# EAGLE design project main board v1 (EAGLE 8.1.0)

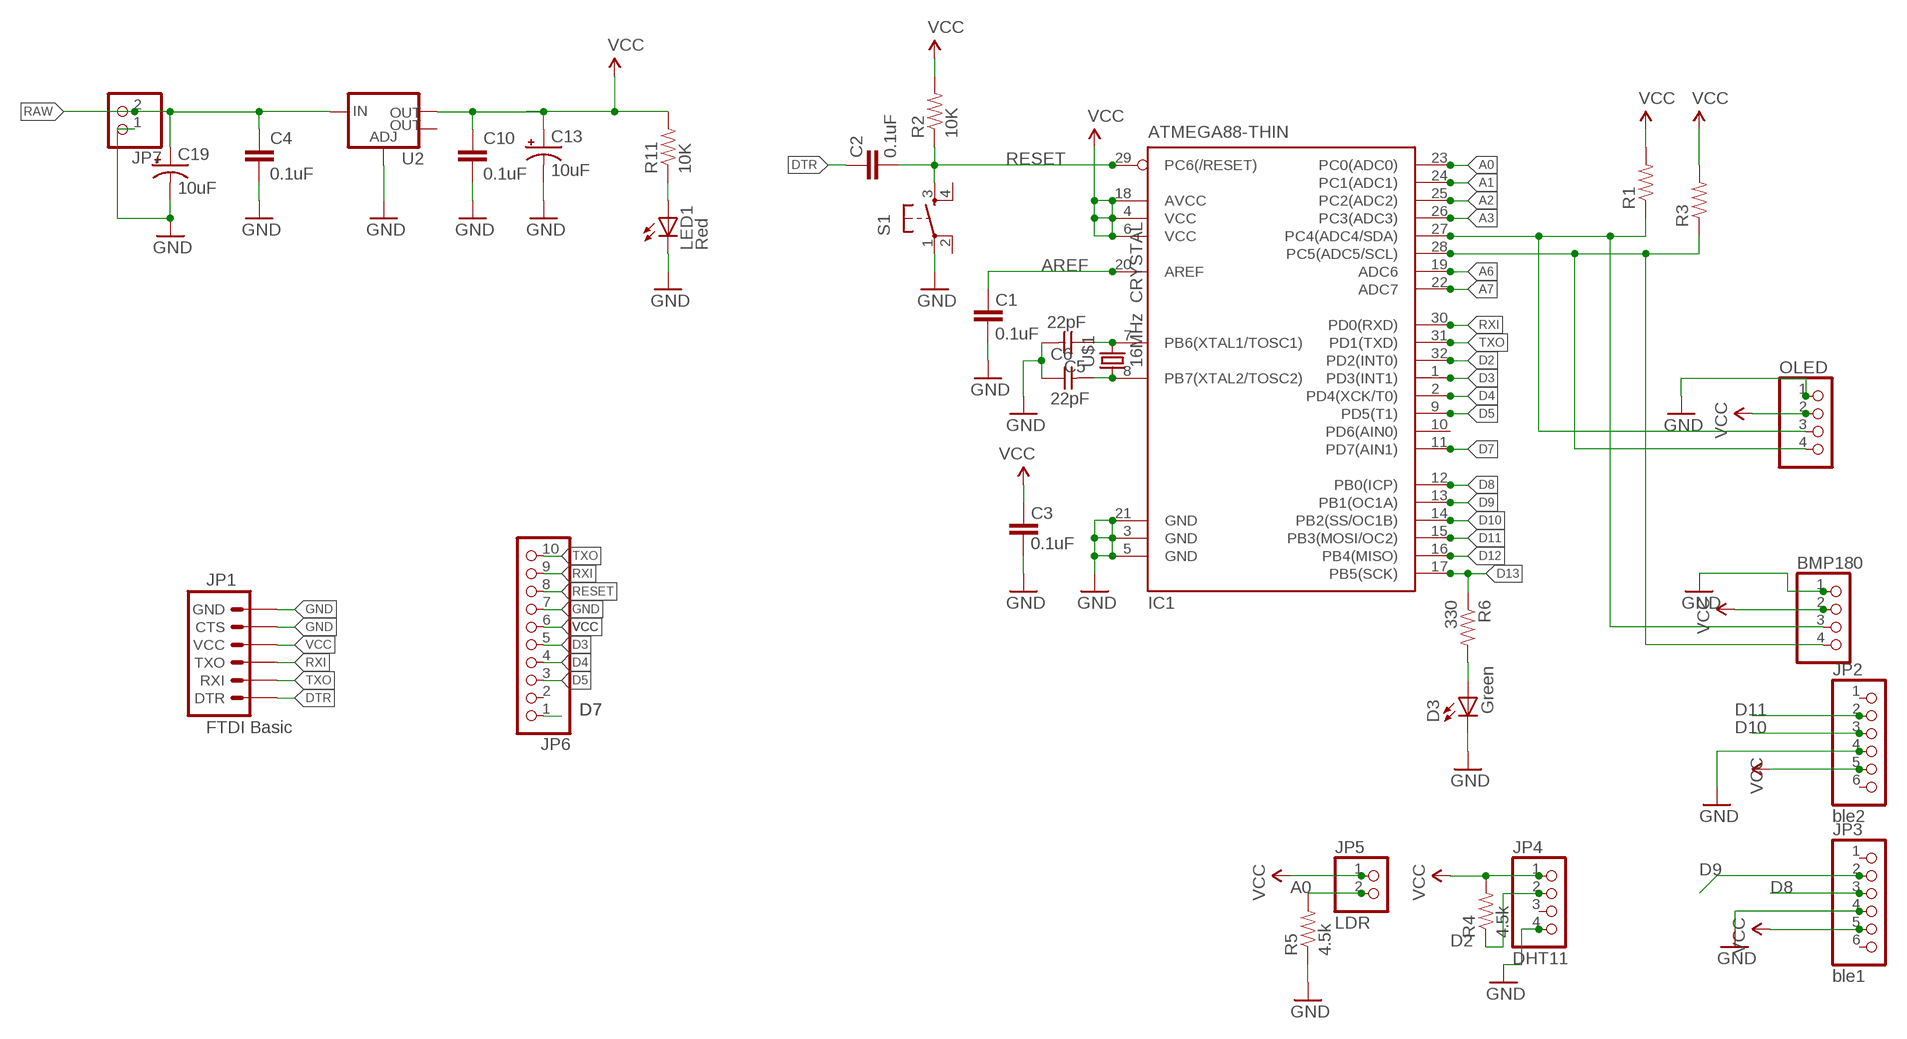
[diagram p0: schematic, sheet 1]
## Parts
BMP180  PINHD-1X4  [1X04]
C1  0.1uF  CAP1206  [1206]
C2  0.1uF  CAP1206  [1206]
C3  0.1uF  CAP1206  [1206]
C4  0.1uF  CAP1206  [1206]
C5  22pF  CAP-UNPOLARIZEDFAB  [C1206FAB]
C6  22pF  CAP-UNPOLARIZEDFAB  [C1206FAB]
C10  0.1uF  CAP1206  [1206]
C13  10uF  CAP_POL1206  [EIA3216]
C19  10uF  CAP_POL1206  [EIA3216]
D3  Green  LED1206  [LED-1206]
IC1  ATMEGA88-THIN  [TQFP32-08THIN]
JP1  FTDI Basic  ARDUINO_SERIAL_PROGRAMLONGPADS  [1X06_LONGPADS]
JP2  ble2  PINHD-1X6  [1X06]
JP3  ble1  PINHD-1X6  [1X06]
JP4  DHT11  PINHD-1X4  [1X04]
JP5  LDR  PINHD-1X2  [1X02]
JP6  PINHD-1X10  [1X10]
JP7  PINHD-1X2  [1X02]
LED1  Red  LED1206  [LED-1206]
OLED  PINHD-1X4  [1X04]
R1  RESISTOR1206  [1206]
R2  10K  RESISTOR1206  [1206]
R3  RESISTOR1206  [1206]
R4  4.5k  RESISTOR1206  [1206]
R5  4.5k  RESISTOR1206  [1206]
R6  330  RESISTOR1206  [1206]
R11  10K  RESISTOR1206  [1206]
S1  6MM_SWITCH6MM_SWITCH  [6MM_SWITCH]
U2  V_REG_LM1117SOT223  [SOT223]
U$1  16MHz CRYSTAL  CRYSTAL  [2-SMD-5X3MM]

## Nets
A0: IC1.23(PC0(ADC0)) JP5.2 R5.2
A1: IC1.24(PC1(ADC1))
A2: IC1.25(PC2(ADC2))
A3: IC1.26(PC3(ADC3))
A4: BMP180.3 IC1.27(PC4(ADC4/SDA)) OLED.3 R1.1
A5: BMP180.4 IC1.28(PC5(ADC5/SCL)) OLED.4 R3.1
A6: IC1.19(ADC6)
A7: IC1.22(ADC7)
AREF: C1.2 IC1.20(AREF)
D2: IC1.32(PD2(INT0)) JP4.2 R4.1
D3: IC1.1(PD3(INT1)) JP6.5
D4: IC1.2(PD4(XCK/T0)) JP6.4
D5: IC1.9(PD5(T1)) JP6.3
D7: IC1.11(PD7(AIN1)) JP6.1
D8: IC1.12(PB0(ICP)) JP3.3
D9: IC1.13(PB1(OC1A)) JP3.2
D10: IC1.14(PB2(SS/OC1B)) JP2.3
D11: IC1.15(PB3(MOSI/OC2)) JP2.2
D12: IC1.16(PB4(MISO))
D13: IC1.17(PB5(SCK)) R6.1
DTR: C2.2 JP1.1(DTR)
GND [vcc]: BMP180.1 C1.1 C3.1 C4.2 C5.2 C6.1 C10.2 C13.C(-) C19.C(-) D3.C IC1.3(GND) IC1.5(GND) IC1.21(GND) JP1.5(CTS) JP1.6(GND) JP2.4 JP3.4 JP4.4 JP6.7 JP7.1 LED1.C OLED.1 R5.1 S1.1(P) U2.1(ADJ)
N$1: C6.2 IC1.8(PB7(XTAL2/TOSC2)) U$1.P$1
N$2: C5.1 IC1.7(PB6(XTAL1/TOSC1)) U$1.P$2
N$3: LED1.A R11.1
N$7: D3.A R6.2
RAW [vcc]: C4.1 C19.A(+) JP7.2 U2.3(IN)
RESET: C2.1 IC1.29(PC6(/RESET)) JP6.8 R2.1 S1.3(S)
RXI: IC1.30(PD0(RXD)) JP1.3(TXO) JP6.9
TXO: IC1.31(PD1(TXD)) JP1.2(RXI) JP6.10
VCC: BMP180.2 C3.2 C10.1 C13.A(+) IC1.4(VCC) IC1.6(VCC) IC1.18(AVCC) JP1.4(VCC) JP2.5 JP3.5 JP4.1 JP5.1 JP6.6 OLED.2 R1.2 R2.2 R3.2 R4.2 R11.2 U2.2(OUT)
Unconnected: IC1.10(PD6(AIN0)) JP2.1 JP2.6 JP3.1 JP3.6 JP4.3 JP6.2 S1.2(P1) S1.4(S1) U2.4(OUT)

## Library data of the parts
BMP180 JP4 OLED = pinhead:PINHD-1X4: PIN HEADER
C1-C4 C10 = SparkFun:CAP: Capacitor
C5 C6 = fab:CAP-UNPOLARIZED
C13 C19 = SparkFun:CAP_POL: Capacitor Polarized
D3 LED1 = Testing:LED: LEDs
IC1 = fab:ATMEGA88-THIN
JP1 = SparkFun:ARDUINO_SERIAL_PROGRAM
JP2 JP3 = pinhead:PINHD-1X6: PIN HEADER
JP5 JP7 = pinhead:PINHD-1X2: PIN HEADER
JP6 = pinhead:PINHD-1X10: PIN HEADER
R1-R6 R11 = SparkFun:RESISTOR: Resistor
S1 = fab:6MM_SWITCH: OMRON SWITCH
U2 = fab:V_REG_LM1117: Voltage Regulator LM1117 Standard adjustable voltage regulator but in SMD form. Spark Fun Electronics SKU : COM-00595; PROD_ID: VREG-08170
U$1 = fab:CRYSTAL

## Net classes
0 default: width 0.203 mm
1 vcc: width 0.254 mm

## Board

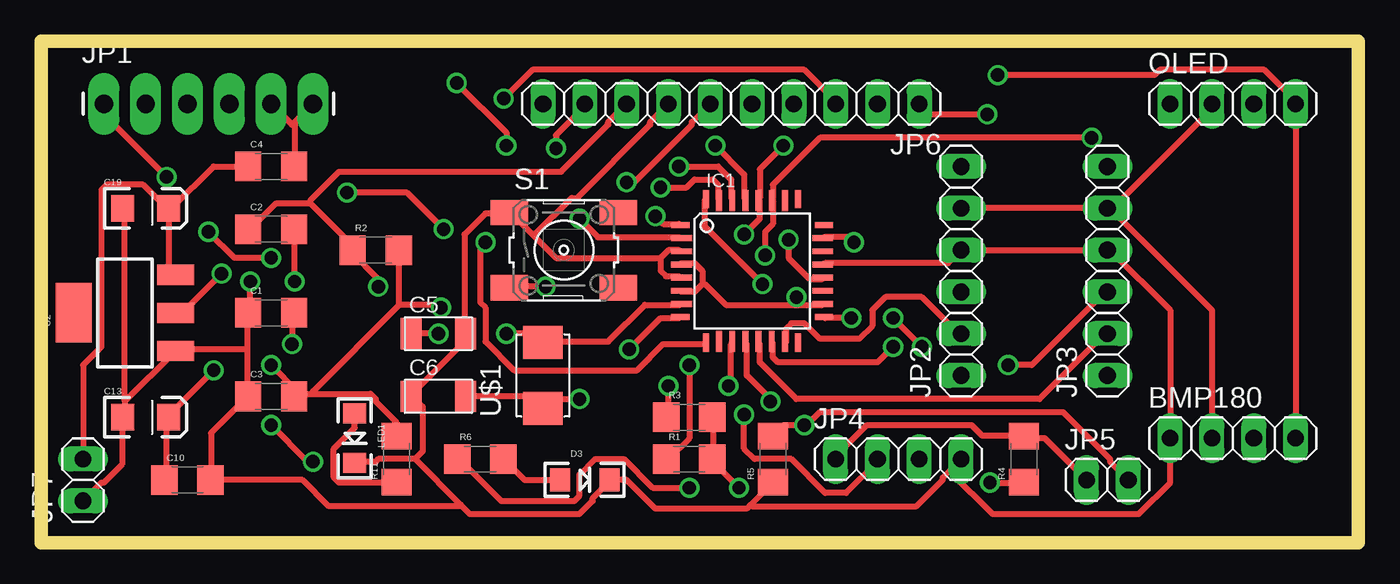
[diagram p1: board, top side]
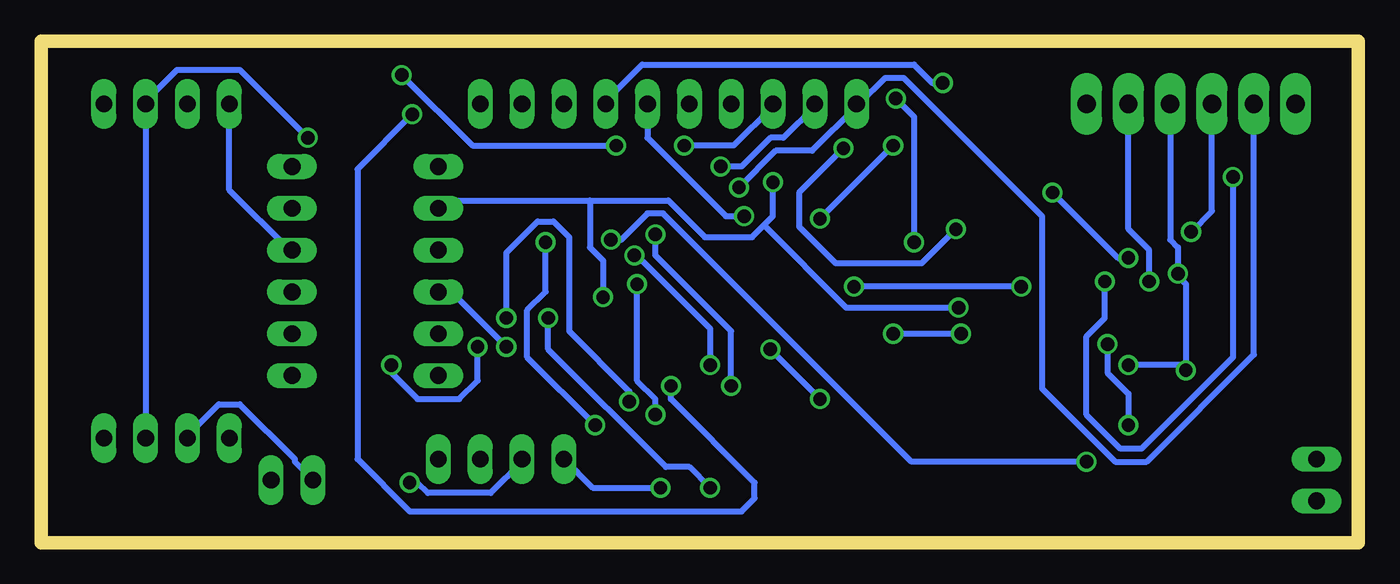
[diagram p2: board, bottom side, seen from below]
Size 80.01 x 30.48 mm. Coordinates in mm from the lower left corner, seen from the top.
Outline: 0,0 80.01,0 80.01,30.48 0,30.48 0,0
Copper layers (1*16): Top 0.035mm / dielectric 1.5mm / Bottom 0.035mm
Design rules "default *": minimum track width 14mil, minimum drill 32mil, track to track 14mil, track to pad 14mil, pad to pad 14mil, via to via 14mil, smd to smd 14mil, copper to edge 40mil, drill to drill 14mil, minimum pad ring 10mil, minimum via ring 8mil, stop-mask expansion 4mil, vias tented up to drill 0mil, thermal gap 10mil

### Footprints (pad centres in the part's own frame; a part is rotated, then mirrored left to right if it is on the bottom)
1X04 = drill 1.016 long: 1 -3.81,0; 2 -1.27,0; 3 1.27,0; 4 3.81,0
1206 = smd 1.6 x 1.8: 1 -1.4,0; 2 1.4,0
C1206FAB = smd 1.27 x 1.905: 1 -1.651,0; 2 1.651,0
EIA3216 = smd 1.4 x 1.6: A 1.4,0; C -1.4,0
LED-1206 = smd 1.2 x 1.4: A -1.5,0; C 1.5,0
TQFP32-08THIN = smd 1.118 x 0.356: 1 -4.369,2.8; 8 -4.369,-2.8; 17 4.369,-2.8; 24 4.369,2.8 | smd 1.27 x 0.356: 2 -4.293,2; 3 -4.293,1.2; 4 -4.293,0.4; 5 -4.293,-0.4; 6 -4.293,-1.2; 7 -4.293,-2; 18 4.293,-2; 19 4.293,-1.2; 20 4.293,-0.4; 21 4.293,0.4; 22 4.293,1.2; 23 4.293,2 | smd 0.356 x 1.118: 9 -2.8,-4.369; 16 2.8,-4.369; 25 2.8,4.369; 32 -2.8,4.369 | smd 0.356 x 1.27: 10 -2,-4.293; 14 1.2,-4.293; 15 2,-4.293; 26 2,4.293; 27 1.2,4.293; 31 -2,4.293 | smd 0.35 x 1.27: 11 -1.2,-4.293; 12 -0.4,-4.293; 13 0.4,-4.293; 28 0.4,4.293; 29 -0.4,4.293; 30 -1.2,4.293
1X06_LONGPADS = drill 1.118 pad 1.88 long: 1 0,0; 2 2.54,0; 3 5.08,0; 4 7.62,0; 5 10.16,0; 6 12.7,0
1X06 = drill 1.016 long: 1 -6.35,0; 2 -3.81,0; 3 -1.27,0; 4 1.27,0; 5 3.81,0; 6 6.35,0
1X02 = drill 1.016 long: 1 -1.27,0; 2 1.27,0
1X10 = drill 1.016 long: 1 -11.43,0; 2 -8.89,0; 3 -6.35,0; 4 -3.81,0; 5 -1.27,0; 6 1.27,0; 7 3.81,0; 8 6.35,0; 9 8.89,0; 10 11.43,0
6MM_SWITCH = smd 2.286 x 1.524: 1 -3.302,2.286; 2 3.302,2.286; 3 -3.302,-2.286; 4 3.302,-2.286
SOT223 = smd 1.219 x 2.235: 1 -2.311,-3.099; 2 0,-3.099; 3 2.311,-3.099 | smd 3.6 x 2.2: 4 0,3.099
2-SMD-5X3MM = smd 2 x 2.4: P$1 -2,0; P$2 2,0

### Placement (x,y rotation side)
BMP180  72.39,6.35 0 top
C1  13.97,13.97 0 top
C2  13.97,19.05 0 top
C3  13.97,8.89 0 top
C4  13.97,22.86 0 top
C5  24.13,12.7 0 top
C6  24.13,8.89 0 top
C10  8.89,3.81 0 top
C13  6.35,7.62 0 top
C19  6.35,20.32 0 top
D3  33.02,3.81 0 top
IC1  43.18,16.51 0 top
JP1  3.81,26.67 0 top
JP2  55.88,16.51 90 top
JP3  64.77,16.51 90 top
JP4  52.07,5.08 0 top
JP5  64.77,3.81 0 top
JP6  41.91,26.67 180 top
JP7  2.54,3.81 90 top
LED1  19.05,6.35 270 top
OLED  72.39,26.67 0 top
R1  39.37,5.08 0 top
R2  20.32,17.78 0 top
R3  39.37,7.62 0 top
R4  59.69,5.08 90 top
R5  44.45,5.08 90 top
R6  26.67,5.08 0 top
R11  21.59,5.08 90 top
S1  31.75,17.78 0 top
U2  5.08,13.97 90 top
U$1  30.48,10.16 90 top

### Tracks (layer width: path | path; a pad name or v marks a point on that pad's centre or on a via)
A0  (via drill 0.81)
  Top 0.356: v49.37,18.26 49.05,18.57 47.62,18.57 IC1.23 | R5.2 44.45,6.51 45.09,7.14 v46.35,7.14 46.51,7.14 47.31,7.94 62.07,7.94 64.93,5.08 64.93,4.92 JP5.2
  Bottom 0.356: v49.37,18.26 49.37,15.24 50.48,14.13 50.48,11.27 v46.35,7.14
A4  (via drill 0.81)
  Top 0.356: v63.82,24.61 47.31,24.61 44.45,21.75 44.45,20.95 IC1.27 44.45,20.8 44.45,19.37 43.97,18.89 v43.97,17.46 | v39.37,10.79 39.37,6.35 38.1,5.08 R1.1
  Bottom 0.356: v63.82,24.61 67.94,28.73 71.75,28.73 73.66,26.83 OLED.3 BMP180.3 | v39.37,10.79 39.37,13.02 43.81,17.46 v43.97,17.46
A5  (via drill 0.81)
  Top 0.356: v42.7,18.73 43.66,19.68 43.66,20.8 IC1.28 43.66,20.95 43.66,22.7 v45.09,24.13 | v38.1,9.53 38.1,7.62 R3.1 | BMP180.4 OLED.4 76.2,26.83 74.3,28.73 67.94,28.73 67.63,28.42 v58.1,28.42
  Bottom 0.356: v42.7,18.73 42.7,17.46 38.1,12.86 v38.1,9.53 | v45.09,24.13 53.82,24.13 v58.1,28.42
AREF  (via drill 0.81)
  Top 0.356: v45.4,18.41 45.4,17.3 46.67,16.03 47.47,16.03 IC1.20 | v16.51,4.92 16.19,4.92 v13.97,7.14 | v15.24,12.06 15.24,13.97 C1.2
  Bottom 0.356: v45.4,18.41 44.77,18.41 43.18,20 42.23,20 27.15,4.92 v16.51,4.92 | v13.97,7.14 13.97,9.05 15.24,10.32 v15.24,12.06
D2  (via drill 0.81)
  Top 0.356: v43.81,15.72 40.32,19.21 40.32,20.8 IC1.32 | v42.7,7.78 42.7,5.71 43.34,5.08 45.56,5.08 47.62,3.02 48.9,3.02 50.8,4.92 JP4.2 | v57.63,3.65 59.69,3.65 R4.1
  Bottom 0.356: v43.81,15.72 43.81,9.84 42.7,8.73 v42.7,7.78 | v57.63,3.65 57.15,3.65 56.52,3.02 52.7,3.02 50.8,4.92 JP4.2
D3  (via drill 0.81)
  Top 0.356: v37.31,19.84 37.78,19.37 38.73,19.37 IC1.1
  Bottom 0.356: v37.31,19.84 38.42,19.84 43.18,24.61 JP6.5
D4  (via drill 0.81)
  Top 0.356: v32.7,19.68 33.81,18.57 38.73,18.57 IC1.2 | v28.26,24.13 28.26,24.92 v25.24,27.94
  Bottom 0.356: v28.26,24.13 v32.7,19.68 | v25.24,27.94 25.88,27.94 26.99,29.05 43.5,29.05 45.72,26.83 JP6.4
D5  (via drill 0.81)
  Top 0.356: v26.99,18.26 26.67,17.94 26.67,14.61 26.99,14.29 26.99,12.22 28.73,10.48 36.2,10.48 37.78,12.06 40.32,12.06 IC1.9 | v28.1,26.99 29.84,28.73 46.35,28.73 48.26,26.83 JP6.3
  Bottom 0.356: v26.99,18.26 26.99,25.88 v28.1,26.99
D7  (via drill 0.81)
  Top 0.356: v41.75,9.53 41.91,9.68 41.91,12.06 IC1.11 | v57.47,26.04 53.98,26.04 JP6.1
  Bottom 0.356: v41.75,9.53 41.75,8.73 36.67,3.65 36.67,2.7 37.47,1.91 57.63,1.91 60.8,5.08 60.8,22.7 v57.47,26.04
D8  (via drill 0.81)
  Top 0.356: v44.29,8.57 44.29,8.73 42.86,10.16 42.86,12.06 IC1.12 | v53.5,11.91 v51.75,13.65 | v58.74,10.79 60.17,10.79 64.61,15.24 JP3.3
  Bottom 0.356: v44.29,8.57 44.29,9.21 47.94,12.86 47.94,18.57 48.9,19.53 49.85,19.53 51.75,17.62 v51.75,13.65 | v53.5,11.91 53.5,9.84 54.61,8.73 57.15,8.73 58.74,10.32 v58.74,10.79
D9
  Top 0.356: JP3.2 64.61,12.7 60.64,8.73 45.88,8.73 43.66,10.95 43.66,12.06 IC1.13
D10  (via drill 0.81)
  Top 0.356: v51.75,11.91 50.8,10.95 44.77,10.95 44.45,11.27 44.45,12.06 IC1.14
  Bottom 0.356: v51.75,11.91 55.09,15.24 JP2.3
D11
  Top 0.356: JP2.2 55.72,12.7 53.5,14.92 51.28,14.92 50.48,14.13 50.48,13.18 49.69,12.38 47.31,12.38 46.35,13.34 45.56,13.34 45.24,13.02 45.24,12.22 IC1.15
D13  (via drill 0.81)
  Top 0.356: v49.21,13.65 47.62,13.65 IC1.17 | v39.37,3.33 37.15,3.33 35.4,5.08 33.66,5.08 32.7,4.13 32.7,2.86 32.38,2.54 27.94,2.54 25.4,5.08 R6.1
  Bottom 0.356: v49.21,13.65 49.21,11.75 42.07,4.6 40.64,4.6 v39.37,3.33
DTR  (via drill 0.81)
  Top 0.356: v15.4,15.88 15.4,19.05 C2.2 | v7.62,22.23 3.81,26.04 JP1.1
  Bottom 0.356: v15.4,15.88 15.4,13.65 16.51,12.54 16.51,7.78 14.45,5.71 13.18,5.71 7.62,11.27 v7.62,22.23
GND  (via drill 0.81)
  Top 0.356: IC1.21 47.62,16.99 55.09,16.99 JP2.4 JP3.4 64.93,17.78 68.58,14.13 BMP180.1 68.58,3.65 66.67,1.75 57.78,1.75 55.24,4.29 JP4.4 54.77,3.97 54.77,3.81 53.18,2.22 43.18,2.22 43.1,2.3 | 5.08,8.57 5.08,7.62 C13.C 4.92,7.46 4.92,4.76 3.81,3.65 3.65,3.65 JP7.1 | 5.08,8.57 8.1,11.59 U2.1 8.26,11.75 12.54,11.75 | 5.08,8.57 5.08,20.32 C19.C | 15.4,25.4 15.4,25.56 JP1.6 | 15.4,25.4 15.4,22.86 C4.2 | JP1.5 15.24,25.4 15.4,25.4 | 12.54,11.75 12.54,9.05 C3.1 12.54,8.89 10.32,6.67 10.32,3.81 C10.2 15.88,3.81 17.46,2.22 25.4,2.22 25.48,2.3 | 12.54,11.75 12.54,13.97 C1.1 12.7,13.97 v12.7,15.88 | 43.1,2.3 44.45,3.65 R5.1 | 43.1,2.3 42.86,2.06 37.31,2.06 35.56,3.81 D3.C 34.45,3.65 33.5,2.7 33.5,2.54 32.7,1.75 26.04,1.75 25.48,2.3 | 22.7,5.08 20.48,5.08 20.32,4.92 19.05,4.92 LED1.C | 22.7,5.08 23.18,5.56 23.18,8.26 22.54,8.89 C6.1 22.54,9.05 25.72,12.22 25.72,12.7 C5.2 25.72,12.86 25.72,18.73 26.99,20 28.42,20 S1.1 28.57,20 29.92,18.65 | 37.62,17.3 37.62,16.51 37.94,16.19 38.73,16.19 IC1.5 | 37.62,17.3 38.1,17.78 38.73,17.78 IC1.3 | 37.62,17.3 31.27,17.3 29.92,18.65 | JP6.7 36.99,25.56 36.99,25.4 32.54,20.95 32.23,20.95 29.92,18.65 | 22.7,5.08 25.48,2.3
  Bottom 0.356: OLED.1 68.58,21.43 64.93,17.78 JP3.4 | JP1.5 13.97,19.05 12.7,17.78 v12.7,15.88
N$1  (via drill 0.81)
  Top 0.356: v35.72,11.75 37.62,13.65 38.73,13.65 IC1.8 | v32.7,8.73 30.96,8.73 30.48,8.26 U$1.P$1 30.96,8.89 C6.2
  Bottom 0.356: v32.7,8.73 v35.72,11.75
N$2  (via drill 0.81)
  Top 0.356: IC1.7 38.73,14.45 36.67,14.45 34.45,12.22 30.48,12.22 U$1.P$2 30.32,12.22 29.84,12.7 v28.26,12.7 | v24.13,12.7 C5.1
  Bottom 0.356: v28.26,12.7 v24.13,12.7
N$3
  Top 0.356: LED1.A 19.05,6.99 17.78,5.71 17.78,3.97 18.1,3.65 21.59,3.65 R11.1
N$7
  Top 0.356: D3.A 29.37,3.81 28.1,5.08 R6.2
RAW
  Top 0.356: C19.A 7.78,20.32 7.78,16.67 8.1,16.35 U2.3 | C4.1 10.48,22.86 7.94,20.32 C19.A | JP7.2 2.54,10.79 3.65,11.91 3.65,21.43 3.97,21.75 6.19,21.75 7.62,20.32 C19.A
RESET  (via drill 0.81)
  Top 0.356: v40.96,24.13 42.7,22.38 42.7,20.95 IC1.29 | 16.35,20.64 18.89,18.1 18.89,17.78 R2.1 18.89,17.62 20.48,16.03 v20.48,15.56 | 16.35,20.64 14.29,20.64 12.7,19.05 C2.1 | v30.64,15.56 28.57,15.56 S1.3 | JP6.8 34.45,25.56 34.45,25.4 31.59,22.54 18.1,22.54 16.35,20.8 16.35,20.64
  Bottom 0.356: v40.96,24.13 37.94,24.13 35.56,26.51 JP6.8 | v20.48,15.56 v30.64,15.56
RXI  (via drill 0.81)
  Top 0.356: v38.73,22.86 41.12,22.86 41.91,22.07 41.91,20.95 IC1.30 | v10.16,18.89 11.75,17.3 v13.97,17.3 | v18.57,21.27 22.23,21.27 v24.45,19.05 | v31.27,23.97 31.27,24.77 33.02,26.51 JP6.9
  Bottom 0.356: v38.73,22.86 37.47,22.86 35.72,24.61 34.92,24.61 33.02,26.51 JP6.9 | JP1.3 8.89,20.16 v10.16,18.89 | v13.97,17.3 14.61,17.3 v18.57,21.27 | v24.45,19.05 26.51,16.99 31.75,16.99 33.97,19.21 33.97,21.27 v31.27,23.97
TXO  (via drill 0.81)
  Top 0.356: v37.62,21.59 39.21,21.59 39.69,22.07 40.8,22.07 41.12,21.75 41.12,20.95 IC1.31
  Bottom 0.356: v37.62,21.59 35.4,23.81 33.18,23.81 30.48,26.51 JP6.10 30.32,26.67 28.73,28.26 27.62,28.26 19.21,19.84 19.21,9.37 14.76,4.92 12.86,4.92 6.35,11.43 JP1.2
VCC  (via drill 0.81)
  Top 0.356: R11.2 21.59,7.3 20.32,8.57 20.32,8.73 20,9.05 16.51,9.05 | 16.51,9.05 15.56,9.05 15.4,8.89 C3.2 15.56,9.21 v13.97,10.79 | 21.75,14.45 21.75,17.78 R2.2 | 21.75,14.45 16.51,9.21 16.51,9.05 | C10.1 7.62,3.81 7.62,7.62 C13.A 7.78,7.78 v10.48,10.48 | U2.2 8.57,13.97 v10.95,16.35 | JP5.1 60.96,6.35 59.69,6.35 R4.2 59.53,6.51 57.15,6.51 56.52,7.14 50.16,7.14 48.26,5.24 JP4.1 | R3.2 40.8,7.62 40.8,5.08 R1.2 40.8,4.92 v42.39,3.33 | 40.16,15.72 39.69,15.24 38.89,15.24 IC1.6 | 40.16,15.72 40.16,16.51 39.69,16.99 38.89,16.99 IC1.4 | 45.88,14.45 41.59,14.45 40.32,15.72 40.16,15.72 | 45.88,14.45 47.47,14.45 IC1.18 | JP3.5 JP2.5 | JP6.6 39.53,25.56 39.53,25.4 36.04,21.91 v35.56,21.91 | BMP180.2 71.12,14.13 64.93,20.32 JP3.5 | OLED.2 71.12,26.35 65.09,20.32 JP3.5 | v45.88,14.92 45.88,14.45 | 21.75,14.45 24.13,14.45 v24.29,14.29
  Bottom 0.356: JP1.4 11.43,18.41 10.95,17.94 v10.95,16.35 10.95,16.19 10.48,15.72 v10.48,10.48 10.64,10.79 v13.97,10.79 | v42.39,3.33 46.51,3.33 JP4.1 | v35.56,21.91 35.56,19.84 36.12,19.29 | 36.12,19.29 36.83,18.57 39.69,18.57 41.91,20.8 46.67,20.8 | 46.67,20.8 55.4,20.8 JP2.5 | v45.88,14.92 45.88,17.14 46.67,17.94 46.67,20.8 | JP5.1 64.61,4.92 64.61,5.08 67.94,8.41 69.22,8.41 71.12,6.51 BMP180.2 | v24.29,14.29 31.11,14.29 36.12,19.29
